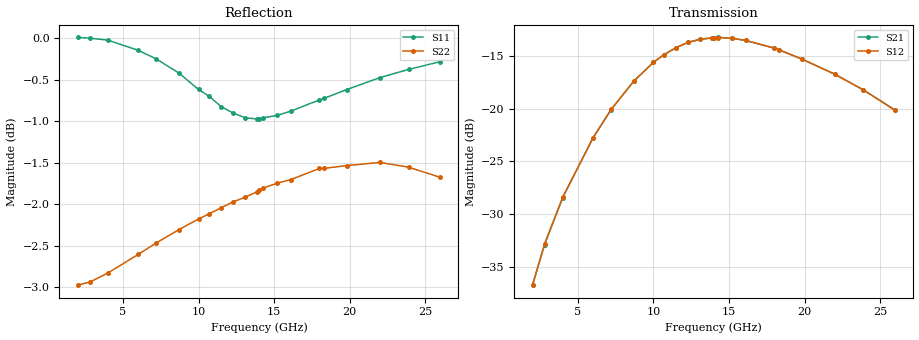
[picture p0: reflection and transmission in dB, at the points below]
! CHUO DENSHI KOGYO Co.,Ltd.
! 1. March 2016
! CKRF7521MM34
! N-channel HJ-FET
! Vds = 0 V Vgs = 0 V
# Hz S  MA  R 50
!  f  S11  S21  S12  S22
!  Hz  MAG  ANG  MAG  ANG  MAG  ANG  MAG  ANG
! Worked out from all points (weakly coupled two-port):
!   241 points, 2 GHz to 26 GHz, reference 50 ohm
!   highest |S21| = -13.26 dB at 14.3 GHz (marker M1); lowest = -36.7 dB at 2 GHz (marker M2)
!   lowest |S11| = -1.0 dB at 13.9 GHz (marker M3), VSWR 17.86, Z = 2.95 + j11.4 ohm
!   |S11| at or under -10 dB: nowhere
!   |S22| runs from -3.0 to -1.5 dB; largest |S21 - S12| = 0.00075
!   S11 on the Smith chart (normalised r, x): 2 GHz: -0.02, -6.08; 7.2 GHz: 0.04, -1.20; 10.7 GHz: 0.05, -0.35; 14 GHz: 0.06, +0.25; 18.3 GHz: 0.09, +1.05; 26 GHz: 0.38, +4.71
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2e9  1.001 -18.7  0.01454 97.6  0.01459 98.1  0.7101 154.5
2.8e9  0.9999 -26.5  0.02265 97.7  0.02286 97.7  0.7131 144.7
4e9  0.9972 -39.1  0.0378 94.2  0.03803 94.8  0.7221 130.7
6e9  0.9833 -62.9  0.0725 82.8  0.07266 82.8  0.7409 108.6
7.2e9  0.9716 -79.7  0.09885 72.7  0.09894 72.7  0.7528 96.5
8.7e9  0.9528 -103.8  0.1348 57.4  0.1349 57.5  0.7668 82.5
1e10  0.9313 -127.7  0.1655 42.4  0.1656 42.6  0.7783 71.2
1.07e10  0.9226 -141.5  0.1801 34.1  0.1802 34.2  0.7838 65.6
1.15e10  0.9094 -157.8  0.1943 24.2  0.1945 24.1  0.7905 59.3
1.23e10  0.9013 -174.1  0.206 14.3  0.2057 14.2  0.797 53.3
1.31e10  0.8954 169.8  0.213 4.4  0.2131 4.4  0.8022 47.4
1.39e10  0.894 154.2  0.2164 -5.2  0.2163 -5.2  0.8084 41.9
1.4e10  0.8943 152.3  0.2166 -6.4  0.2168 -6.3  0.8097 41.2
1.43e10  0.8955 146.8  0.2174 -9.8  0.2171 -9.8  0.8125 39.1
1.52e10  0.8983 130.9  0.2154 -19.9  0.2153 -19.9  0.8178 32.9
1.61e10  0.9037 116.4  0.2102 -29.4  0.2104 -29.3  0.8219 27.1
1.8e10  0.9179 90.3  0.1933 -47.6  0.1934 -47.6  0.8347 14.7
1.83e10  0.9199 86.7  0.1899 -50.2  0.19 -50.2  0.8348 12.8
1.98e10  0.9311 70.4  0.1718 -62.8  0.172 -62.8  0.838 3.6
2.2e10  0.9467 50.9  0.1455 -79.3  0.1454 -79.2  0.8417 -9.8
2.39e10  0.9575 37.0  0.1224 -92.9  0.1225 -92.7  0.8362 -21.2
2.6e10  0.9679 23.8  0.09825 -108.0  0.09791 -108.1  0.8245 -33.7
